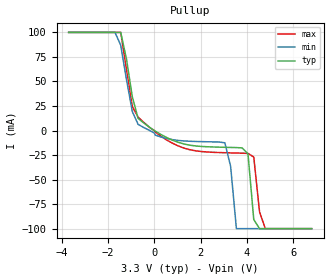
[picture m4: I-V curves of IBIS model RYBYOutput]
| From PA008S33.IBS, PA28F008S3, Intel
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|****************Ready/Busy Output Model*****************************
[Model]   RYBYOutput
Model_type   Output
|   For RY/BY#
Vinl = 0.8V
Vinh = 2.0V
| Variable   typ   min   max
C_comp   9.61p   NA   11.6p
[Voltage Range]   3.3V   3.0V   3.6V
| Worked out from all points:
|   slope of the pullup table from 0 to 0.495 V, typ, clamps not added: 74.9 ohm
[Pulldown]
| [Pullup] and [Pulldown] IV curves include only the current through
| the channels of output driver transistors when outputs are enabled
| with OE# = VIL.  Although the output driver transistors have np and
| pn diodes inherently created by CMOS IC fabrication between the
| drain and bulk of n-channel and p-channel CMOS transistors,
| the current through these junction diodes is not included in
| [Pullup] or [Pulldown].  Instead that drain/bulk diode current is
| included in the [POWER_clamp] or [GND_clamp] sections, which are
| not dependent on the state of OE# or output data value.  The RY/BY#
| Pulldown information is not provided for this device.  The table
| below is for the compatibility with some IBIS parsers.
|Voltage   I(typ)   I(min)   I(max)
-3.3V     0A         0A         0A
0V        0A         0A         0A
3.3V      0A         0A         0A
7V        0A         0A         0A
[GND_clamp]
| The RY/BY# pin is always active and does NOT float to tri-state when
| the chip is deselected or when the data outputs are disabled.
| Therefore, the table below is included for the compatibility with
| some IBIS parsers.
|Voltage   I(typ)   I(min)   I(max)
-3.3V     0A         0A         0A
0V        0A         0A         0A
3.3V      0A         0A         0A
7V        0A         0A         0A
[Pullup]
| (Voltages for [Pullup] and [POWER_clamp] are specified with
| negative respect to Vcc.  Reference the IBIS documentation
| for more information regarding Vtable = Vcc - Voutput.
| This method keeps -Vds constant for the values in all three
| columns across a line of the table.)
| [Pullup] and [Pulldown] IV curves include only the current through
| the channels of output driver transistors when outputs are enabled
| with OE# = VIL.  Although the output driver transistors have np and
| pn diodes inherently created by CMOS IC fabrication between the
| drain and bulk of n-channel and p-channel CMOS transistors,
| the current through these junction diodes is not included in
| [Pullup] or [Pulldown].  Instead that drain/bulk diode current is
| included in the [POWER_clamp] or [GND_clamp] sections, which are
| not dependent on the state of OE# or output data value.
|Voltage  I(typ)   I(min)   I(max)
-3.7V     100mA      100mA      100mA
-1.45V    100mA      86.91mA    100mA
-950mV    34.46mA    19.43mA    24.44mA
-700mV    12.4mA     6.32mA     13.67mA
3.05V     -17.1mA    -12.53mA   -22.62mA
3.3V      -17.24mA   -36.49mA   -22.79mA
3.55V     -17.37mA   -100mA     -22.95mA
4.05V     -23.73mA   -100mA     -23.32mA
4.3V      -90.68mA   -100mA     -27.01mA
4.55V     -100mA     -100mA     -82.93mA
4.8V      -100mA     -100mA     -100mA
6.8V      -100mA     -100mA     -100mA
[POWER_clamp]
| The RY/BY# pin is always active and does NOT float to tri-state when
| the chip is deselected or when the data outputs are disabled.
| Therefore, the table below is included for the compatibility with
| some IBIS parsers.
|Voltage   I(typ)   I(min)   I(max)
-3.3V     0A         0A         0A
0V        0A         0A         0A
3.3V      0A         0A         0A
7V        0A         0A         0A
[Ramp]
| The RY/BY# Ramp information is not provided for this device.  The table
| below is for the compatibility with some IBIS parsers.
| Variable   typ   min   max
 dV/dt_r   0V/0ns   0V/0ns   0V/0ns
 dV/dt_f   0V/0ns   0V/0ns   0V/0ns
